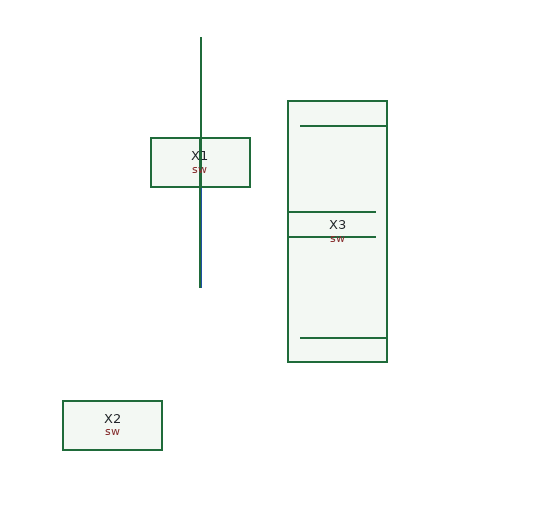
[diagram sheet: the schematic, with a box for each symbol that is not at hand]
v {xschem version=3.1.0 file_version=1.2 }
G {}
K {}
V {}
S {}
E {}
N 170 -150 200 -150 {
lab=#net1}
N 200 -150 200 -80 {
lab=#net1}
N 200 -80 230 -80 {
lab=#net1}
N 200 -60 230 -60 {
lab=#net2}
N 200 -60 200 20 {
lab=#net2}
N 170 20 200 20 {
lab=#net2}
N 90 -190 90 -20 {
lab=#net3}
N 90 -220 90 -190 {
lab=#net3}
C {/home/97ms/uci/ip/dac/1.schematics/sw.sym} 20 -80 0 0 {name=X1}
C {/home/97ms/uci/ip/dac/1.schematics/sw.sym} 20 90 0 0 {name=X2}
C {/home/97ms/uci/ip/dac/1.schematics/sw.sym} 220 0 0 0 {name=X3}
